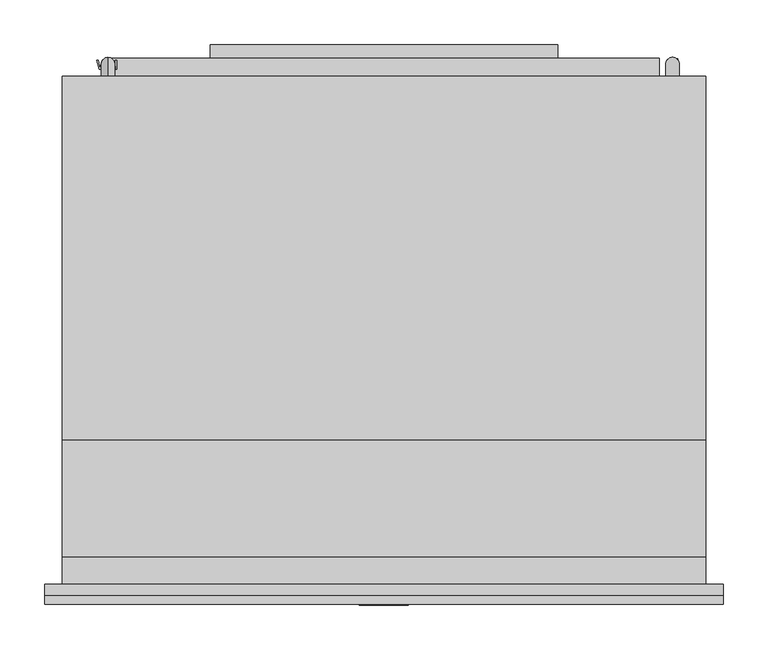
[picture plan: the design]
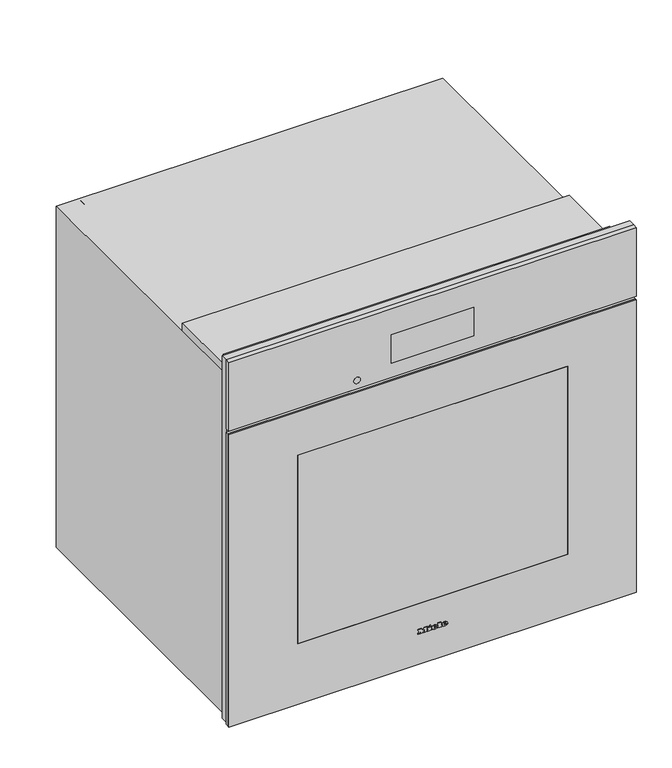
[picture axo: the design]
"""IFC4 building model written with IfcOpenShell, lengths in millimetres: proxy geometry."""

from ifc_helpers import new_model, si_unit, point, frame, frame_2d, origin, place, context, project, spatial, polyline, circle_curve, ellipse_curve, trimmed, segment, composite_curve, outline, extrude, faceted_brep, source, transform, mapped, element, save
from ifc_brep_helpers import plane_surface, cylinder_surface, revolved_surface, extruded_surface, advanced_brep


def specialty_equipment_5303c2b9(model_context):
    return source(origin(), model_context, "Body", "SolidModel", [
        advanced_brep(
        [(21.28, -23.0, 73.133), (21.28, -23.0, 74.042), (27.301, -23.0, 74.042), (16.825, -23.0, 74.042), (19.3, -23.0, 71.0), (27.148, -23.0, 73.133), (24.43, -23.0, 73.133), (22.288, -23.0, 72.125), (21.28, -23.0, 75.194), (21.28, -23.0, 76.175), (22.819, -23.0, 76.175), (22.819, -23.0, 75.194), (21.28, -22.0, 73.133), (22.288, -22.0, 72.125), (24.43, -22.0, 73.133), (27.148, -22.0, 73.133), (19.3, -22.0, 71.0), (16.825, -22.0, 74.042), (27.301, -22.0, 74.042), (21.28, -22.0, 74.042), (21.28, -22.0, 75.194), (22.819, -22.0, 75.194), (22.819, -22.0, 76.175), (21.28, -22.0, 76.175)],
        [
            (0, 1),
            (1, 2),
            (2, 3, ellipse_curve(frame((22.063, -23.0, 74.042), z_axis=(0.0, -1.0, 0.0), x_axis=(-1.0, 0.0, 0.0)), 5.238, 4.329)),
            (3, 4, circle_curve(frame((20.3080491, -23.0, 74.348), z_axis=(0.0, -1.0, 0.0), x_axis=(0.0, 0.0, -1.0)), 3.4964649)),
            (4, 5, circle_curve(frame((21.9581428, -23.0, 76.724), z_axis=(0.0, -1.0, 0.0), x_axis=(0.0, 0.0, -1.0)), 6.3110933)),
            (5, 6),
            (6, 7, circle_curve(frame((22.7279412, -23.0, 73.97), z_axis=(0.0, 1.0, 0.0), x_axis=(0.0, 0.0, -1.0)), 1.896727)),
            (7, 0, circle_curve(frame((22.288, -23.0, 73.133), z_axis=(0.0, 1.0, 0.0), x_axis=(0.0, 0.0, -1.0)), 1.008)),
            (8, 9),
            (9, 10, circle_curve(frame((22.0495, -23.0, 76.175), z_axis=(0.0, 1.0, 0.0), x_axis=(0.0, 0.0, -1.0)), 0.7695)),
            (10, 11),
            (11, 8),
            (12, 13, circle_curve(frame((22.288, -22.0, 73.133), z_axis=(0.0, -1.0, 0.0), x_axis=(0.0, 0.0, -1.0)), 1.008)),
            (13, 14, circle_curve(frame((22.7279412, -22.0, 73.97), z_axis=(0.0, -1.0, 0.0), x_axis=(0.0, 0.0, -1.0)), 1.896727)),
            (14, 15),
            (15, 16, circle_curve(frame((21.9581428, -22.0, 76.724), z_axis=(0.0, 1.0, 0.0), x_axis=(0.0, 0.0, -1.0)), 6.3110933)),
            (16, 17, circle_curve(frame((20.3080491, -22.0, 74.348), z_axis=(0.0, 1.0, 0.0), x_axis=(0.0, 0.0, -1.0)), 3.4964649)),
            (17, 18, ellipse_curve(frame((22.063, -22.0, 74.042), z_axis=(0.0, 1.0, 0.0), x_axis=(-1.0, 0.0, 0.0)), 5.238, 4.329)),
            (18, 19),
            (19, 12),
            (20, 21),
            (21, 22),
            (22, 23, circle_curve(frame((22.0495, -22.0, 76.175), z_axis=(0.0, -1.0, 0.0), x_axis=(0.0, 0.0, -1.0)), 0.7695)),
            (23, 20),
            (0, 12),
            (19, 1),
            (18, 2),
            (5, 15),
            (14, 6),
            (17, 3),
            (13, 7),
            (16, 4),
            (8, 20),
            (23, 9),
            (22, 10),
            (21, 11),
        ],
        [
            plane_surface(frame((21.28, -23.0, 74.042), z_axis=(0.0, -1.0, 0.0), x_axis=(0.0, 0.0, 1.0))),
            plane_surface(frame((21.28, -22.0, 74.042), z_axis=(0.0, 1.0, 0.0), x_axis=(0.0, 0.0, -1.0))),
            plane_surface(frame((21.28, -23.0, 73.133), z_axis=(1.0, 0.0, 0.0), x_axis=(0.0, 1.0, 0.0))),
            plane_surface(frame((21.28, -23.0, 74.042), z_axis=(0.0, 0.0, -1.0), x_axis=(0.0, 1.0, 0.0))),
            plane_surface(frame((27.148, -23.0, 73.133), z_axis=(0.0, 0.0, 1.0), x_axis=(0.0, 1.0, 0.0))),
            extruded_surface(trimmed(ellipse_curve(frame((22.063, -21.0, 74.042), z_axis=(0.0, -1.0, 0.0), x_axis=(-1.0, 0.0, 0.0)), 5.238, 4.329), [point((27.301, -21.0, 74.042))], [point((16.825, -21.0, 74.042))], True, "CARTESIAN"), (0.0, -1.0, 0.0), 1.0),
            revolved_surface(polyline([(22.7279412, -22.0, 72.073273), (22.7279412, -23.0, 72.073273)]), (22.7279412, -22.0, 73.97), (0.0, 1.0, 0.0)),
            revolved_surface(polyline([(22.288, -22.0, 72.125), (22.288, -23.0, 72.125)]), (22.288, -22.0, 73.133), (0.0, 1.0, 0.0)),
            cylinder_surface(frame((20.3080491, -22.0, 74.348), z_axis=(0.0, -1.0, 0.0), x_axis=(0.0, 0.0, -1.0)), 3.4964649),
            cylinder_surface(frame((21.9581428, -22.0, 76.724), z_axis=(0.0, -1.0, 0.0), x_axis=(0.0, 0.0, -1.0)), 6.3110933),
            plane_surface(frame((21.28, -23.0, 75.194), z_axis=(1.0, 0.0, 0.0), x_axis=(0.0, 1.0, 0.0))),
            revolved_surface(polyline([(22.0495, -22.0, 75.4055), (22.0495, -23.0, 75.4055)]), (22.0495, -22.0, 76.175), (0.0, 1.0, 0.0)),
            plane_surface(frame((22.819, -23.0, 76.175), z_axis=(-1.0, 0.0, 0.0), x_axis=(0.0, 1.0, 0.0))),
            plane_surface(frame((22.819, -23.0, 75.194), z_axis=(0.0, 0.0, 1.0), x_axis=(0.0, 1.0, 0.0))),
        ],
        [
            (0, [[1, 2, 3, 4, 5, 6, 7, 8], [9, 10, 11, 12]]),
            (1, [[13, 14, 15, 16, 17, 18, 19, 20], [21, 22, 23, 24]]),
            (2, [[-1, 25, -20, 26]]),
            (3, [[-2, -26, -19, 27]]),
            (4, [[-6, 28, -15, 29]]),
            (5, [[-3, -27, -18, 30]]),
            (6, [[-7, -29, -14, 31]]),
            (7, [[-8, -31, -13, -25]]),
            (8, [[-4, -30, -17, 32]]),
            (9, [[-5, -32, -16, -28]]),
            (10, [[-9, 33, -24, 34]]),
            (11, [[-10, -34, -23, 35]]),
            (12, [[-11, -35, -22, 36]]),
            (13, [[-12, -36, -21, -33]]),
        ],
    ),
        advanced_brep(
        [(2.497, -23.0, 73.133), (2.497, -23.0, 74.042), (8.518, -23.0, 74.042), (-1.958, -23.0, 74.042), (0.517, -23.0, 71.0), (8.365, -23.0, 73.133), (5.647, -23.0, 73.133), (3.505, -23.0, 72.125), (2.497, -23.0, 75.194), (2.497, -23.0, 76.175), (4.036, -23.0, 76.175), (4.036, -23.0, 75.194), (2.497, -22.0, 73.133), (3.505, -22.0, 72.125), (5.647, -22.0, 73.133), (8.365, -22.0, 73.133), (0.517, -22.0, 71.0), (-1.958, -22.0, 74.042), (8.518, -22.0, 74.042), (2.497, -22.0, 74.042), (2.497, -22.0, 75.194), (4.036, -22.0, 75.194), (4.036, -22.0, 76.175), (2.497, -22.0, 76.175)],
        [
            (0, 1),
            (1, 2),
            (2, 3, ellipse_curve(frame((3.28, -23.0, 74.042), z_axis=(0.0, -1.0, 0.0), x_axis=(-1.0, 0.0, 0.0)), 5.238, 4.329)),
            (3, 4, circle_curve(frame((1.5250491, -23.0, 74.348), z_axis=(0.0, -1.0, 0.0), x_axis=(0.0, 0.0, -1.0)), 3.4964649)),
            (4, 5, circle_curve(frame((3.1751428, -23.0, 76.724), z_axis=(0.0, -1.0, 0.0), x_axis=(0.0, 0.0, -1.0)), 6.3110933)),
            (5, 6),
            (6, 7, circle_curve(frame((3.9449412, -23.0, 73.97), z_axis=(0.0, 1.0, 0.0), x_axis=(0.0, 0.0, -1.0)), 1.896727)),
            (7, 0, circle_curve(frame((3.505, -23.0, 73.133), z_axis=(0.0, 1.0, 0.0), x_axis=(0.0, 0.0, -1.0)), 1.008)),
            (8, 9),
            (9, 10, circle_curve(frame((3.2665, -23.0, 76.175), z_axis=(0.0, 1.0, 0.0), x_axis=(0.0, 0.0, -1.0)), 0.7695)),
            (10, 11),
            (11, 8),
            (12, 13, circle_curve(frame((3.505, -22.0, 73.133), z_axis=(0.0, -1.0, 0.0), x_axis=(0.0, 0.0, -1.0)), 1.008)),
            (13, 14, circle_curve(frame((3.9449412, -22.0, 73.97), z_axis=(0.0, -1.0, 0.0), x_axis=(0.0, 0.0, -1.0)), 1.896727)),
            (14, 15),
            (15, 16, circle_curve(frame((3.1751428, -22.0, 76.724), z_axis=(0.0, 1.0, 0.0), x_axis=(0.0, 0.0, -1.0)), 6.3110933)),
            (16, 17, circle_curve(frame((1.5250491, -22.0, 74.348), z_axis=(0.0, 1.0, 0.0), x_axis=(0.0, 0.0, -1.0)), 3.4964649)),
            (17, 18, ellipse_curve(frame((3.28, -22.0, 74.042), z_axis=(0.0, 1.0, 0.0), x_axis=(-1.0, 0.0, 0.0)), 5.238, 4.329)),
            (18, 19),
            (19, 12),
            (20, 21),
            (21, 22),
            (22, 23, circle_curve(frame((3.2665, -22.0, 76.175), z_axis=(0.0, -1.0, 0.0), x_axis=(0.0, 0.0, -1.0)), 0.7695)),
            (23, 20),
            (0, 12),
            (19, 1),
            (18, 2),
            (5, 15),
            (14, 6),
            (17, 3),
            (13, 7),
            (16, 4),
            (8, 20),
            (23, 9),
            (22, 10),
            (21, 11),
        ],
        [
            plane_surface(frame((2.497, -23.0, 74.042), z_axis=(0.0, -1.0, 0.0), x_axis=(0.0, 0.0, 1.0))),
            plane_surface(frame((2.497, -22.0, 74.042), z_axis=(0.0, 1.0, 0.0), x_axis=(0.0, 0.0, -1.0))),
            plane_surface(frame((2.497, -23.0, 73.133), z_axis=(1.0, 0.0, 0.0), x_axis=(0.0, 1.0, 0.0))),
            plane_surface(frame((2.497, -23.0, 74.042), z_axis=(0.0, 0.0, -1.0), x_axis=(0.0, 1.0, 0.0))),
            plane_surface(frame((8.365, -23.0, 73.133), z_axis=(0.0, 0.0, 1.0), x_axis=(0.0, 1.0, 0.0))),
            extruded_surface(trimmed(ellipse_curve(frame((3.28, -21.0, 74.042), z_axis=(0.0, -1.0, 0.0), x_axis=(-1.0, 0.0, 0.0)), 5.238, 4.329), [point((8.518, -21.0, 74.042))], [point((-1.958, -21.0, 74.042))], True, "CARTESIAN"), (0.0, -1.0, 0.0), 1.0),
            revolved_surface(polyline([(3.9449412, -22.0, 72.073273), (3.9449412, -23.0, 72.073273)]), (3.9449412, -22.0, 73.97), (0.0, 1.0, 0.0)),
            revolved_surface(polyline([(3.505, -22.0, 72.125), (3.505, -23.0, 72.125)]), (3.505, -22.0, 73.133), (0.0, 1.0, 0.0)),
            cylinder_surface(frame((1.5250491, -22.0, 74.348), z_axis=(0.0, -1.0, 0.0), x_axis=(0.0, 0.0, -1.0)), 3.4964649),
            cylinder_surface(frame((3.1751428, -22.0, 76.724), z_axis=(0.0, -1.0, 0.0), x_axis=(0.0, 0.0, -1.0)), 6.3110933),
            plane_surface(frame((2.497, -23.0, 75.194), z_axis=(1.0, 0.0, 0.0), x_axis=(0.0, 1.0, 0.0))),
            revolved_surface(polyline([(3.2665, -22.0, 75.4055), (3.2665, -23.0, 75.4055)]), (3.2665, -22.0, 76.175), (0.0, 1.0, 0.0)),
            plane_surface(frame((4.036, -23.0, 76.175), z_axis=(-1.0, 0.0, 0.0), x_axis=(0.0, 1.0, 0.0))),
            plane_surface(frame((4.036, -23.0, 75.194), z_axis=(0.0, 0.0, 1.0), x_axis=(0.0, 1.0, 0.0))),
        ],
        [
            (0, [[1, 2, 3, 4, 5, 6, 7, 8], [9, 10, 11, 12]]),
            (1, [[13, 14, 15, 16, 17, 18, 19, 20], [21, 22, 23, 24]]),
            (2, [[-1, 25, -20, 26]]),
            (3, [[-2, -26, -19, 27]]),
            (4, [[-6, 28, -15, 29]]),
            (5, [[-3, -27, -18, 30]]),
            (6, [[-7, -29, -14, 31]]),
            (7, [[-8, -31, -13, -25]]),
            (8, [[-4, -30, -17, 32]]),
            (9, [[-5, -32, -16, -28]]),
            (10, [[-9, 33, -24, 34]]),
            (11, [[-10, -34, -23, 35]]),
            (12, [[-11, -35, -22, 36]]),
            (13, [[-12, -36, -21, -33]]),
        ],
    ),
        extrude(outline(polyline([(79.469, -7.34), (78.011, -6.656), (79.433, -3.605), (80.891, -4.28), (79.469, -7.34)])), frame((0.0, -23.0, 0.0), z_axis=(0.0, 1.0, 0.0), x_axis=(0.0, 0.0, 1.0)), (0.0, 0.0, 1.0), 1.0),
        extrude(outline(polyline([(77.813, -9.563), (76.202, -9.563), (76.202, -8.492), (72.512, -8.492), (72.512, -9.563), (71.0, -9.563), (71.0, -2.462), (72.512, -2.462), (72.512, -3.506), (77.813, -3.506), (77.813, -9.563)])), frame((0.0, -23.0, 0.0), z_axis=(0.0, 1.0, 0.0), x_axis=(0.0, 0.0, 1.0)), (0.0, 0.0, 1.0), 1.0),
        extrude(outline(polyline([(78.533, 9.022), (78.533, 10.102), (72.512, 10.102), (72.512, 9.022), (71.0, 9.022), (71.0, 16.321), (72.512, 16.321), (72.512, 15.214), (80.0, 15.214), (80.0, 9.022), (78.533, 9.022)])), frame((0.0, -23.0, 0.0), z_axis=(0.0, 1.0, 0.0), x_axis=(0.0, 0.0, 1.0)), (0.0, 0.0, 1.0), 1.0),
        extrude(outline(polyline([(78.533, -27.5), (78.533, -26.411), (72.512, -26.411), (72.512, -27.5), (71.0, -27.5), (71.0, -23.54), (72.512, -23.54), (72.512, -24.62), (76.3341247, -24.62), (71.0, -20.597), (76.4402223, -16.556), (72.512, -16.556), (72.512, -17.663), (71.0, -17.663), (71.0, -10.481), (72.512, -10.481), (72.512, -11.624), (78.533, -11.624), (78.533, -10.481), (80.0, -10.481), (80.0, -15.962), (76.625, -18.59), (80.0, -21.227), (80.0, -27.5), (78.533, -27.5)])), frame((0.0, -23.0, 0.0), z_axis=(0.0, 1.0, 0.0), x_axis=(0.0, 0.0, 1.0)), (0.0, 0.0, 1.0), 1.0),
        extrude(outline(polyline([(378.5, -18.0), (-378.5, -18.0), (-378.5, -13.0), (378.5, -13.0), (378.5, -18.0)])), frame((0.0, 0.0, 11.0), z_axis=(0.0, 0.0, 1.0), x_axis=(1.0, 0.0, 0.0)), (0.0, 0.0, 1.0), 574.0),
        extrude(outline(polyline([(585.0, 378.5), (585.0, -378.5), (11.0, -378.5), (11.0, 378.5), (585.0, 378.5)]), holes=[polyline([(500.0, 250.5), (130.0, 250.5), (130.0, -250.5), (500.0, -250.5), (500.0, 250.5)])]), frame((0.0, -22.0, 0.0), z_axis=(0.0, 1.0, 0.0), x_axis=(0.0, 0.0, 1.0)), (0.0, 0.0, 1.0), 4.0),
        extrude(outline(polyline([(-250.5, -18.0), (250.5, -18.0), (250.5, -22.0), (-250.5, -22.0), (-250.5, -18.0)])), frame((0.0, 0.0, 130.0), z_axis=(0.0, 0.0, 1.0), x_axis=(1.0, 0.0, 0.0)), (0.0, 0.0, 1.0), 370.0),
        extrude(outline(polyline([(-76.5, -21.0), (76.5, -21.0), (76.5, -22.0), (-76.5, -22.0), (-76.5, -21.0)])), frame((0.0, 0.0, 620.0), z_axis=(0.0, 0.0, 1.0), x_axis=(1.0, 0.0, 0.0)), (0.0, 0.0, 1.0), 56.0),
        faceted_brep([(378.5, -13.0, 727.0), (378.5, -13.0, 592.0), (-378.5, -13.0, 592.0), (-378.5, -13.0, 727.0), (378.5, -22.0, 592.0), (-378.5, -22.0, 592.0), (378.5, -22.0, 727.0), (-378.5, -22.0, 727.0), (76.5, -22.0, 676.0), (76.5, -22.0, 620.0), (-76.5, -22.0, 620.0), (-76.5, -22.0, 676.0), (-76.5, -21.0, 620.0), (-76.5, -21.0, 676.0), (76.5, -21.0, 676.0), (76.5, -21.0, 620.0)], [[[0, 1, 2, 3]], [[4, 5, 2, 1]], [[6, 7, 5, 4], [8, 9, 10, 11]], [[12, 13, 11, 10]], [[13, 14, 8, 11]], [[7, 6, 0, 3]], [[5, 7, 3, 2]], [[6, 4, 1, 0]], [[14, 13, 12, 15]], [[14, 15, 9, 8]], [[15, 12, 10, 9]]]),
        extrude(outline(composite_curve([segment(trimmed(circle_curve(frame_2d((609.0, -140.5745637)), 6.0), [point((609.0, -146.5745637))], [point((609.0, -134.5745637))], False, "CARTESIAN"), True, "CONTINUOUS"), segment(trimmed(circle_curve(frame_2d((609.0, -140.5745637)), 6.0), [point((609.0, -134.5745637))], [point((609.0, -146.5745637))], False, "CARTESIAN"), True, "CONTINUOUS")], self_intersect=False)), frame((0.0, -22.5, 0.0), z_axis=(0.0, 1.0, 0.0), x_axis=(0.0, 0.0, 1.0)), (0.0, 0.0, 1.0), 1.0),
        extrude(outline(polyline([(327.856335, 586.4164958), (327.856335, 576.4164958), (322.0, 576.4164958), (322.0, 577.4164958), (326.856335, 577.4164958), (326.856335, 580.9164958), (323.9061855, 580.9164958), (323.9061855, 581.9164958), (326.856335, 581.9164958), (326.856335, 585.4164958), (322.0, 585.4164958), (322.0, 586.4164958), (327.856335, 586.4164958)])), frame((0.0, 0.0, 585.0), z_axis=(0.0, 0.0, 1.0), x_axis=(1.0, 0.0, 0.0)), (0.0, 0.0, 1.0), 1.0),
        extrude(outline(polyline([(320.5, 576.4164958), (315.5, 576.4164958), (315.5, 577.4164958), (319.3952098, 577.4164958), (319.3952098, 586.4164958), (320.5, 586.4164958), (320.5, 576.4164958)])), frame((0.0, 0.0, 585.0), z_axis=(0.0, 0.0, 1.0), x_axis=(1.0, 0.0, 0.0)), (0.0, 0.0, 1.0), 1.0),
        advanced_brep(
        [(329.5, 567.0, 616.0), (314.5, 567.0, 616.0), (329.5, 580.5, 616.0), (314.5, 580.5, 616.0), (329.5, 580.5, 586.0), (314.5, 580.5, 586.0)],
        [
            (0, 1, circle_curve(frame((322.0, 567.0, 616.0), z_axis=(0.0, -1.0, 0.0), x_axis=(-1.0, 0.0, 0.0)), 7.5)),
            (1, 0, circle_curve(frame((322.0, 567.0, 616.0), z_axis=(0.0, -1.0, 0.0), x_axis=(-1.0, 0.0, 0.0)), 7.5)),
            (0, 2),
            (2, 3, ellipse_curve(frame((322.0, 580.5, 616.0), z_axis=(0.0, -0.7071067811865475, 0.7071067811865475), x_axis=(0.0, -0.7071067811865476, -0.7071067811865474)), 10.6066017, 7.5)),
            (3, 1),
            (3, 2, ellipse_curve(frame((322.0, 580.5, 616.0), z_axis=(0.0, -0.7071067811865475, 0.7071067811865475), x_axis=(0.0, -0.7071067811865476, -0.7071067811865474)), 10.6066017, 7.5)),
            (4, 5, circle_curve(frame((322.0, 580.5, 586.0), z_axis=(0.0, 0.0, -1.0), x_axis=(-1.0, 0.0, 0.0)), 7.5)),
            (5, 4, circle_curve(frame((322.0, 580.5, 586.0), z_axis=(0.0, 0.0, -1.0), x_axis=(-1.0, 0.0, 0.0)), 7.5)),
            (2, 4),
            (5, 3),
        ],
        [
            plane_surface(frame((322.0, 567.0, 616.0), z_axis=(0.0, -1.0, 0.0), x_axis=(-1.0, 0.0, 0.0))),
            cylinder_surface(frame((322.0, 567.0, 616.0), z_axis=(0.0, -1.0, 0.0), x_axis=(-1.0, 0.0, 0.0)), 7.5),
            plane_surface(frame((322.0, 580.5, 586.0), z_axis=(0.0, 0.0, -1.0), x_axis=(-1.0, 0.0, 0.0))),
            cylinder_surface(frame((322.0, 580.5, 616.0), z_axis=(0.0, 0.0, 1.0), x_axis=(-1.0, 0.0, 0.0)), 7.5),
        ],
        [
            (0, [[1, 2]]),
            (1, [[-1, 3, 4, 5]]),
            (1, [[-2, -5, 6, -3]]),
            (2, [[7, 8]]),
            (3, [[-4, 9, -8, 10]]),
            (3, [[-6, -10, -7, -9]]),
        ],
    ),
        extrude(outline(polyline([(-299.6202453, 584.6579034), (-298.3679159, 584.6579034), (-298.3679159, 574.6085654), (-299.6149696, 574.6085654), (-299.6149696, 578.0788376), (-301.2450476, 579.7089156), (-305.0884371, 574.6085654), (-306.7066233, 574.6085654), (-302.2301778, 580.5490092), (-306.5150452, 584.6543198), (-304.7713587, 584.6543198), (-299.6202453, 579.7190632), (-299.6202453, 584.6579034)])), frame((0.0, 0.0, 614.0), z_axis=(0.0, 0.0, 1.0), x_axis=(1.0, 0.0, 0.0)), (0.0, 0.0, 1.0), 1.0),
        extrude(outline(polyline([(-307.9869589, 584.6543198), (-306.6749258, 584.6543198), (-309.4307199, 574.6085654), (-310.9513148, 574.6085654), (-313.5193527, 583.4401554), (-316.2529808, 574.6085654), (-317.6013152, 574.6085654), (-320.3417347, 584.6663082), (-319.072273, 584.6663082), (-316.9158246, 576.0172661), (-314.4357517, 584.6663082), (-312.5770153, 584.6663082), (-310.0671021, 576.0346114), (-307.9869589, 584.6543198)])), frame((0.0, 0.0, 614.0), z_axis=(0.0, 0.0, 1.0), x_axis=(1.0, 0.0, 0.0)), (0.0, 0.0, 1.0), 1.0),
        advanced_brep(
        [(-308.0, 573.0, 615.0), (-308.0, 588.0, 615.0), (-308.0, 573.0, 637.5), (-308.0, 588.0, 652.5), (-308.0, 559.0, 637.5), (-308.0, 559.0, 652.5)],
        [
            (0, 1, circle_curve(frame((-308.0, 580.5, 615.0), z_axis=(0.0, 0.0, -1.0), x_axis=(0.0, 1.0, 0.0)), 7.5)),
            (1, 0, circle_curve(frame((-308.0, 580.5, 615.0), z_axis=(0.0, 0.0, -1.0), x_axis=(0.0, 1.0, 0.0)), 7.5)),
            (0, 2),
            (2, 3, ellipse_curve(frame((-308.0, 580.5, 645.0), z_axis=(0.0, 0.7071067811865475, -0.7071067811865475), x_axis=(0.0, -0.7071067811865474, -0.7071067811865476)), 10.6066017, 7.5)),
            (3, 1),
            (3, 2, ellipse_curve(frame((-308.0, 580.5, 645.0), z_axis=(0.0, 0.7071067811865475, -0.7071067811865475), x_axis=(0.0, -0.7071067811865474, -0.7071067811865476)), 10.6066017, 7.5)),
            (4, 5, circle_curve(frame((-308.0, 559.0, 645.0), z_axis=(0.0, -1.0, 0.0), x_axis=(0.0, 0.0, 1.0)), 7.5)),
            (5, 4, circle_curve(frame((-308.0, 559.0, 645.0), z_axis=(0.0, -1.0, 0.0), x_axis=(0.0, 0.0, 1.0)), 7.5)),
            (2, 4),
            (5, 3),
        ],
        [
            plane_surface(frame((-308.0, 580.5, 615.0), z_axis=(0.0, 0.0, -1.0), x_axis=(-1.0, 0.0, 0.0))),
            cylinder_surface(frame((-308.0, 580.5, 615.0), z_axis=(0.0, 0.0, -1.0), x_axis=(0.0, 1.0, 0.0)), 7.5),
            plane_surface(frame((-308.0, 559.0, 645.0), z_axis=(0.0, -1.0, 0.0), x_axis=(-1.0, 0.0, 0.0))),
            cylinder_surface(frame((-308.0, 580.5, 645.0), z_axis=(0.0, 1.0, 0.0), x_axis=(0.0, 0.0, 1.0)), 7.5),
        ],
        [
            (0, [[1, 2]]),
            (1, [[-1, 3, 4, 5]]),
            (1, [[-2, -5, 6, -3]]),
            (2, [[7, 8]]),
            (3, [[-4, 9, -8, 10]]),
            (3, [[-6, -10, -7, -9]]),
        ],
    ),
        faceted_brep([(353.5, 25.0, 593.0), (-353.5, 25.0, 593.0), (-353.5, 25.0, 15.0), (353.5, 25.0, 15.0), (-312.5, 25.0, 526.0), (312.5, 25.0, 526.0), (312.5, 25.0, 103.0), (-312.5, 25.0, 103.0), (353.5, 0.0, 593.0), (-353.5, 0.0, 593.0), (-353.5, 0.0, 15.0), (353.5, 0.0, 15.0), (359.0, 0.0, 670.0), (359.0, 0.0, 0.0), (359.0, 567.0, 0.0), (359.0, 567.0, 670.0), (-359.0, 0.0, 0.0), (-359.0, 0.0, 670.0), (-359.0, 567.0, 670.0), (-359.0, 567.0, 0.0), (-307.0, 567.0, 0.0), (-307.0, 587.0, 0.0), (307.0, 587.0, 0.0), (307.0, 567.0, 0.0), (-307.0, 587.0, 584.0), (307.0, 587.0, 584.0), (312.5, 433.0, 526.0), (-312.5, 433.0, 526.0), (-312.5, 433.0, 103.0), (312.5, 433.0, 103.0), (-307.0, 567.0, 584.0), (307.0, 567.0, 584.0)], [[[0, 1, 2, 3], [4, 5, 6, 7]], [[1, 0, 8, 9]], [[2, 1, 9, 10]], [[0, 3, 11, 8]], [[12, 13, 14, 15]], [[16, 17, 18, 19]], [[13, 16, 19, 20, 21, 22, 23, 14]], [[22, 21, 24, 25]], [[17, 12, 15, 18]], [[16, 13, 12, 17], [9, 8, 11, 10]], [[26, 27, 28, 29]], [[27, 26, 5, 4]], [[28, 27, 4, 7]], [[29, 28, 7, 6]], [[26, 29, 6, 5]], [[3, 2, 10, 11]], [[25, 24, 30, 31]], [[20, 30, 24, 21]], [[14, 23, 31, 30, 20, 19, 18, 15]], [[31, 23, 22, 25]]]),
        extrude(outline(polyline([(-194.0, 602.0), (194.0, 602.0), (194.0, 587.0), (-194.0, 587.0), (-194.0, 602.0)])), frame((0.0, 0.0, 230.0), z_axis=(0.0, 0.0, 1.0), x_axis=(1.0, 0.0, 0.0)), (0.0, 0.0, 1.0), 158.0),
        extrude(outline(polyline([(30.0, 705.0), (30.0, 686.0), (161.0, 686.0), (161.0, 670.0), (0.0, 670.0), (0.0, 705.0), (30.0, 705.0)])), frame((-359.0, 0.0, 0.0), z_axis=(1.0, 0.0, 0.0), x_axis=(0.0, 1.0, 0.0)), (0.0, 0.0, 1.0), 718.0),
        extrude(outline(polyline([(15.0, 378.5), (727.0, 378.5), (727.0, -378.5), (15.0, -378.5), (15.0, -353.5), (593.0, -353.5), (593.0, 353.5), (15.0, 353.5), (15.0, 378.5)])), frame((0.0, -13.0, 0.0), z_axis=(0.0, 1.0, 0.0), x_axis=(0.0, 0.0, 1.0)), (0.0, 0.0, 1.0), 13.0),
    ])


if __name__ == "__main__":
    model = new_model("IFC4")
    model_context = context("Model", 3, world=origin())
    ifc_project = project(units=[si_unit("LENGTHUNIT", "METRE", prefix="MILLI")], contexts=[model_context])
    site = spatial("IfcSite", under=ifc_project)
    building = spatial("IfcBuilding", under=site)
    placement = place(None, origin())
    specialty_equipment_shape = specialty_equipment_5303c2b9(model_context)
    element("IfcBuildingElementProxy", 1, Name="Specialty Equipment", at=placement, inside=building, context=model_context, shape_type="MappedRepresentation", body=[
        mapped(specialty_equipment_shape, transform((0.0, 0.0, 0.0), x_axis=(1.0, 0.0, 0.0), y_axis=(0.0, 1.0, 0.0), z_axis=(0.0, 0.0, 1.0))),
    ])
    save(model, "model.ifc")
